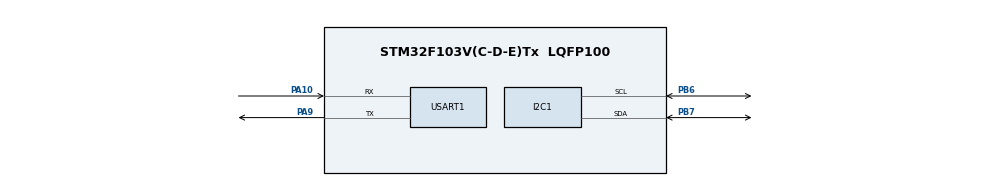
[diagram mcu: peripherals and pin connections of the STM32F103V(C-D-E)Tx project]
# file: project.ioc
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Mcu.Family=STM32F1
Mcu.Name=STM32F103V(C-D-E)Tx
Mcu.Package=LQFP100
NVIC.PriorityGroup=NVIC_PRIORITYGROUP_4
OSC_IN.Mode=HSE-External-Oscillator
OSC_IN.Signal=RCC_OSC_IN
OSC_OUT.Mode=HSE-External-Oscillator
OSC_OUT.Signal=RCC_OSC_OUT
PA10.Mode=Asynchronous
PA10.Signal=USART1_RX
PA9.Mode=Asynchronous
PA9.Signal=USART1_TX
PB6.Mode=I2C
PB6.Signal=I2C1_SCL
PB7.Mode=I2C
PB7.Signal=I2C1_SDA
ProjectManager.TargetToolchain=MDK-ARM V5
RCC.AHBFreq_Value=72000000
RCC.APB1CLKDivider=RCC_HCLK_DIV2
RCC.APB1Freq_Value=36000000
RCC.APB1TimCLKDivider=1
RCC.APB1TimFreq_Value=36000000
RCC.APB2Freq_Value=72000000
RCC.APB2TimFreq_Value=72000000
RCC.HCLKFreq_Value=72000000
RCC.HSIState=RCC_HSI_ON
RCC.PLLMUL=RCC_PLL_MUL9
RCC.PLLSourceVirtual=RCC_PLLSOURCE_HSE
RCC.SYSCLKFreq_VALUE=72000000
RCC.SYSCLKSource=RCC_SYSCLKSOURCE_PLLCLK
RCC.USBFreq_Value=72000000
board=project

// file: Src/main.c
/**
  ******************************************************************************
  * File Name          : main.c
  * Description        : Main program body
  ******************************************************************************
  *
  * COPYRIGHT(c) 2016 STMicroelectronics
  *
  * Redistribution and use in source and binary forms, with or without modification,
  * are permitted provided that the following conditions are met:
  *   1. Redistributions of source code must retain the above copyright notice,
  *      this list of conditions and the following disclaimer.
  *   2. Redistributions in binary form must reproduce the above copyright notice,
  *      this list of conditions and the following disclaimer in the documentation
  *      and/or other materials provided with the distribution.
  *   3. Neither the name of STMicroelectronics nor the names of its contributors
  *      may be used to endorse or promote products derived from this software
  *      without specific prior written permission.
  *
  * THIS SOFTWARE IS PROVIDED BY THE COPYRIGHT HOLDERS AND CONTRIBUTORS "AS IS"
  * AND ANY EXPRESS OR IMPLIED WARRANTIES, INCLUDING, BUT NOT LIMITED TO, THE
  * IMPLIED WARRANTIES OF MERCHANTABILITY AND FITNESS FOR A PARTICULAR PURPOSE ARE
  * DISCLAIMED. IN NO EVENT SHALL THE COPYRIGHT HOLDER OR CONTRIBUTORS BE LIABLE
  * FOR ANY DIRECT, INDIRECT, INCIDENTAL, SPECIAL, EXEMPLARY, OR CONSEQUENTIAL
  * DAMAGES (INCLUDING, BUT NOT LIMITED TO, PROCUREMENT OF SUBSTITUTE GOODS OR
  * SERVICES; LOSS OF USE, DATA, OR PROFITS; OR BUSINESS INTERRUPTION) HOWEVER
  * CAUSED AND ON ANY THEORY OF LIABILITY, WHETHER IN CONTRACT, STRICT LIABILITY,
  * OR TORT (INCLUDING NEGLIGENCE OR OTHERWISE) ARISING IN ANY WAY OUT OF THE USE
  * OF THIS SOFTWARE, EVEN IF ADVISED OF THE POSSIBILITY OF SUCH DAMAGE.
  *
  ******************************************************************************
  */
#include "stm32f1xx_hal.h"
#include "i2c.h"
#include "usart.h"
#include "gpio.h"
#include "BMP388.h"

/* USER CODE BEGIN PV */
/* Private variables ---------------------------------------------------------*/

/* USER CODE END PV */

void SystemClock_Config(void);

/* USER CODE BEGIN PFP */
/* Private function prototypes -----------------------------------------------*/

/* USER CODE END PFP */

int main(void)
{

  /* USER CODE BEGIN 1 */
  uint8_t u8RegData=0;
	PRESS_EN_SENSOR_TYPY enPressureType;
	int32_t s32PressureVal = 0, s32TemperatureVal = 0, s32AltitudeVal = 0;

  /* USER CODE END 1 */

  /* MCU Configuration----------------------------------------------------------*/

  /* Reset of all peripherals, Initializes the Flash interface and the Systick. */
  HAL_Init();

  /* Configure the system clock */
  SystemClock_Config();

  /* Initialize all configured peripherals */
  MX_GPIO_Init();
  MX_I2C1_Init();
  MX_USART1_UART_Init();

  /* USER CODE BEGIN 2 */
	pressSensorInit( &enPressureType );
  	if(PRESS_EN_SENSOR_TYPY_BMP388 == enPressureType)
	{
		printf("Pressure sersor is BMP388\n");
	}
	else
	{
		printf("Pressure sersor NULL\n");
	}
	printf("\r\n /-------------------------------------------------------------/\r\n ");

  printf("\n\r who am I  \r\n");
  HAL_I2C_Mem_Read(&hi2c1, 0xD0, 0x75, I2C_MEMADD_SIZE_8BIT, &u8RegData, 1, 0x10);
  printf("\n\r  MPU9250 WAI 0x%02x \r\n",u8RegData);//0x71
  u8RegData=0;
  HAL_I2C_Mem_Read(&hi2c1, 0x28<<1, 0x00, I2C_MEMADD_SIZE_8BIT, &u8RegData, 1, 0x10);
  printf("\n\r  BNO055 WAI 0x%02x \r\n",u8RegData);//0xA0
  u8RegData=0;
  HAL_I2C_Mem_Read(&hi2c1, 0xEE, 0xD0, I2C_MEMADD_SIZE_8BIT, &u8RegData, 1, 0x10);
  printf("\n\r  BMP280 WAI 0x%02x \r\n",u8RegData);//0x58
  u8RegData=0;
  HAL_I2C_Mem_Read(&hi2c1, 0xEE, 0x00, I2C_MEMADD_SIZE_8BIT, &u8RegData, 1, 0x10);
  printf("\n\r  DF-BMP388 WAI 0x%02x \r\n",u8RegData);//0x50
  u8RegData=0;
  HAL_I2C_Mem_Read(&hi2c1, 0x76<<1, 0x00, I2C_MEMADD_SIZE_8BIT, &u8RegData, 1, 0x10);
  printf("\n\r  W-BMP388 WAI 0x%02x \r\n",u8RegData);//0x50
  /* USER CODE END 2 */

  /* Infinite loop */
  /* USER CODE BEGIN WHILE */
  delay(500);
  while (1)
  {
  /* USER CODE END WHILE */

  /* USER CODE BEGIN 3 */
  pressSensorDataGet(&s32TemperatureVal, &s32PressureVal, &s32AltitudeVal);
  printf("\r\n Pressure: %.2f  Altitude: %.2f Temperature: %.1f\r\n",
          (float)s32PressureVal/100,
          (float)s32AltitudeVal/100,
          (float)s32TemperatureVal/100);
  delay(200);
  }
  /* USER CODE END 3 */

}

/** System Clock Configuration
*/
void SystemClock_Config(void)
{

  RCC_OscInitTypeDef RCC_OscInitStruct;
  RCC_ClkInitTypeDef RCC_ClkInitStruct;

  RCC_OscInitStruct.OscillatorType = RCC_OSCILLATORTYPE_HSI;
  RCC_OscInitStruct.HSIState = RCC_HSI_ON;
  RCC_OscInitStruct.HSICalibrationValue = 16;
  RCC_OscInitStruct.PLL.PLLState = RCC_PLL_NONE;
  HAL_RCC_OscConfig(&RCC_OscInitStruct);

  RCC_ClkInitStruct.ClockType = RCC_CLOCKTYPE_HCLK|RCC_CLOCKTYPE_SYSCLK
                              |RCC_CLOCKTYPE_PCLK1|RCC_CLOCKTYPE_PCLK2;
  RCC_ClkInitStruct.SYSCLKSource = RCC_SYSCLKSOURCE_HSI;
  RCC_ClkInitStruct.AHBCLKDivider = RCC_SYSCLK_DIV1;
  RCC_ClkInitStruct.APB1CLKDivider = RCC_HCLK_DIV1;
  RCC_ClkInitStruct.APB2CLKDivider = RCC_HCLK_DIV1;
  HAL_RCC_ClockConfig(&RCC_ClkInitStruct, FLASH_LATENCY_0);

  HAL_SYSTICK_Config(HAL_RCC_GetHCLKFreq()/1000);

  HAL_SYSTICK_CLKSourceConfig(SYSTICK_CLKSOURCE_HCLK);

  /* SysTick_IRQn interrupt configuration */
  HAL_NVIC_SetPriority(SysTick_IRQn, 0, 0);
}

/************************ (C) COPYRIGHT STMicroelectronics *****END OF FILE****/
